One B-rep face of a CAD part: STEP entity #1342.
In plain terms, the planar face has unit normal (1, 0, 0).
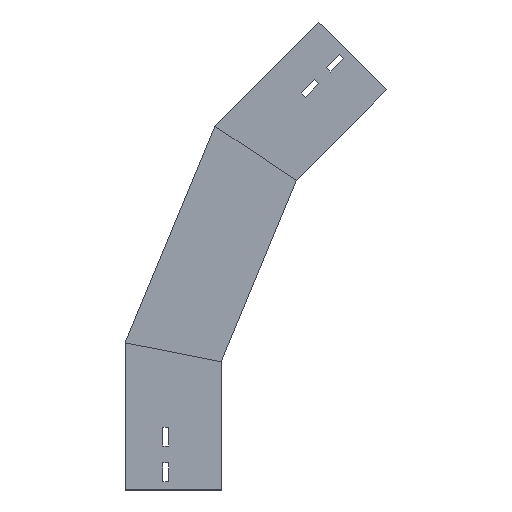
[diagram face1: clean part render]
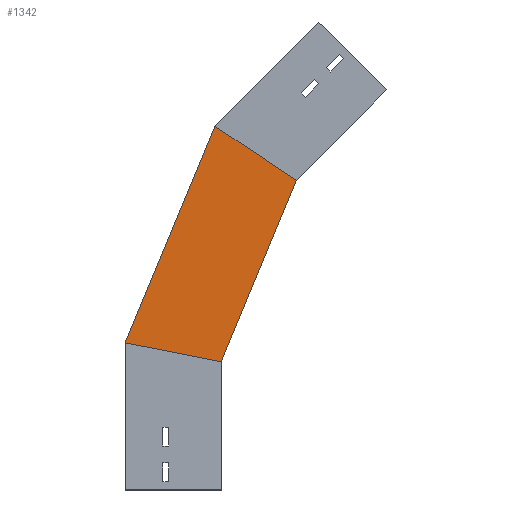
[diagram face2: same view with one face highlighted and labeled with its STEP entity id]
Its self-contained STEP definition (entity closure, numbers rounded to 3 decimals):
#48 = CARTESIAN_POINT ( 'NONE',  ( 0., 9.458, 127.166 ) ) ;
#143 = ORIENTED_EDGE ( 'NONE', *, *, #1187, .T. ) ;
#148 = ORIENTED_EDGE ( 'NONE', *, *, #301, .F. ) ;
#212 = ORIENTED_EDGE ( 'NONE', *, *, #761, .F. ) ;
#301 = EDGE_CURVE ( 'NONE', #1339, #707, #346, .T. ) ;
#346 = LINE ( 'NONE', #1006, #1198 ) ;
#418 = AXIS2_PLACEMENT_3D ( 'NONE', #48, #1447, #1340 ) ;
#438 = CARTESIAN_POINT ( 'NONE',  ( 0., 0., 150. ) ) ;
#443 = DIRECTION ( 'NONE',  ( 0., -0.981, -0.195 ) ) ;
#512 = CARTESIAN_POINT ( 'NONE',  ( 0., 9.458, 127.166 ) ) ;
#539 = VECTOR ( 'NONE', #854, 1000. ) ;
#573 = EDGE_LOOP ( 'NONE', ( #143, #1488, #212, #148 ) ) ;
#617 = CARTESIAN_POINT ( 'NONE',  ( 0., 113.395, 170.218 ) ) ;
#627 = VECTOR ( 'NONE', #951, 1000. ) ;
#632 = CARTESIAN_POINT ( 'NONE',  ( 0., 112.5, 172.378 ) ) ;
#639 = PLANE ( 'NONE',  #418 ) ;
#651 = VECTOR ( 'NONE', #1437, 1000. ) ;
#707 = VERTEX_POINT ( 'NONE', #438 ) ;
#720 = CARTESIAN_POINT ( 'NONE',  ( 0., -129.335, 334.885 ) ) ;
#745 = VERTEX_POINT ( 'NONE', #946 ) ;
#761 = EDGE_CURVE ( 'NONE', #707, #745, #856, .T. ) ;
#819 = LINE ( 'NONE', #617, #627 ) ;
#854 = DIRECTION ( 'NONE',  ( 0., -0.831, -0.556 ) ) ;
#856 = LINE ( 'NONE', #512, #651 ) ;
#946 = CARTESIAN_POINT ( 'NONE',  ( 0., -88.017, 362.492 ) ) ;
#951 = DIRECTION ( 'NONE',  ( 0., -0.383, 0.924 ) ) ;
#959 = EDGE_CURVE ( 'NONE', #1230, #745, #1074, .T. ) ;
#1006 = CARTESIAN_POINT ( 'NONE',  ( 0., -28.701, 144.291 ) ) ;
#1074 = LINE ( 'NONE', #720, #539 ) ;
#1089 = FACE_OUTER_BOUND ( 'NONE', #573, .T. ) ;
#1187 = EDGE_CURVE ( 'NONE', #1339, #1230, #819, .T. ) ;
#1198 = VECTOR ( 'NONE', #443, 1000. ) ;
#1230 = VERTEX_POINT ( 'NONE', #1407 ) ;
#1339 = VERTEX_POINT ( 'NONE', #632 ) ;
#1340 = DIRECTION ( 'NONE',  ( 0., 0., -1. ) ) ;
#1342 = ADVANCED_FACE ( 'NONE', ( #1089 ), #639, .T. ) ;
#1407 = CARTESIAN_POINT ( 'NONE',  ( 0., 7.356, 426.218 ) ) ;
#1437 = DIRECTION ( 'NONE',  ( 0., -0.383, 0.924 ) ) ;
#1447 = DIRECTION ( 'NONE',  ( 1., 0., 0. ) ) ;
#1488 = ORIENTED_EDGE ( 'NONE', *, *, #959, .T. ) ;
